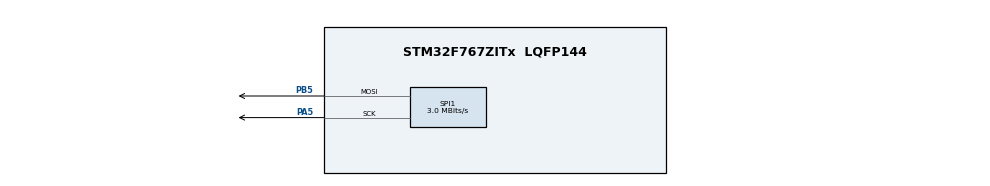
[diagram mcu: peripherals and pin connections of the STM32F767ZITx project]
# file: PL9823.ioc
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Dma.Request0=SPI1_TX
Dma.SPI1_TX.0.Direction=DMA_MEMORY_TO_PERIPH
Dma.SPI1_TX.0.FIFOMode=DMA_FIFOMODE_DISABLE
Dma.SPI1_TX.0.Instance=DMA2_Stream3
Dma.SPI1_TX.0.MemDataAlignment=DMA_MDATAALIGN_BYTE
Dma.SPI1_TX.0.MemInc=DMA_MINC_ENABLE
Dma.SPI1_TX.0.Mode=DMA_CIRCULAR
Dma.SPI1_TX.0.PeriphDataAlignment=DMA_PDATAALIGN_BYTE
Dma.SPI1_TX.0.PeriphInc=DMA_PINC_DISABLE
Dma.SPI1_TX.0.Priority=DMA_PRIORITY_VERY_HIGH
Mcu.Family=STM32F7
Mcu.Name=STM32F767ZITx
Mcu.Package=LQFP144
NVIC.DMA2_Stream3_IRQn=true\:0\:0\:false\:false\:true\:false\:true
NVIC.PriorityGroup=NVIC_PRIORITYGROUP_4
NVIC.SPI1_IRQn=true\:0\:0\:false\:false\:true\:true\:true
PA5.Mode=TX_Only_Simplex_Unidirect_Master
PA5.Signal=SPI1_SCK
PB5.Mode=TX_Only_Simplex_Unidirect_Master
PB5.Signal=SPI1_MOSI
ProjectManager.HeapSize=0x200
ProjectManager.StackSize=0x400
ProjectManager.TargetToolchain=TrueSTUDIO
RCC.AHBCLKDivider=RCC_SYSCLK_DIV4
RCC.AHBFreq_Value=24000000
RCC.APB1Freq_Value=24000000
RCC.APB1TimFreq_Value=24000000
RCC.APB2Freq_Value=24000000
RCC.APB2TimFreq_Value=24000000
RCC.CortexFreq_Value=24000000
RCC.HCLKFreq_Value=24000000
RCC.HSE_VALUE=25000000
RCC.HSI_VALUE=16000000
RCC.LSE_VALUE=32768
RCC.PLLM=8
RCC.PLLN=96
RCC.SYSCLKFreq_VALUE=96000000
RCC.SYSCLKSource=RCC_SYSCLKSOURCE_PLLCLK
RCC.USBFreq_Value=96000000
RCC.VCOOutputFreq_Value=192000000
SPI1.BaudRatePrescaler=SPI_BAUDRATEPRESCALER_8
SPI1.CalculateBaudRate=3.0 MBits/s
SPI1.DataSize=SPI_DATASIZE_8BIT
SPI1.Direction=SPI_DIRECTION_2LINES
SPI1.Mode=SPI_MODE_MASTER
SPI1.VirtualType=VM_MASTER
board=custom

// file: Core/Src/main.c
/* USER CODE BEGIN Header */
/**
 ******************************************************************************
 * @file           : main.c
 * @brief          : Main program body
 ******************************************************************************
 * @attention
 *
 * <h2><center>&copy; Copyright (c) 2020 STMicroelectronics.
 * All rights reserved.</center></h2>
 *
 * This software component is licensed by ST under BSD 3-Clause license,
 * the "License"; You may not use this file except in compliance with the
 * License. You may obtain a copy of the License at:
 *                        opensource.org/licenses/BSD-3-Clause
 *
 ******************************************************************************
 */
/* USER CODE END Header */
#include "main.h"

/* USER CODE BEGIN PD */
#define T0H 0b10000000
#define T1H 0b11110000
#define NUMBER_OF_LEDS 4
/* USER CODE END PD */

SPI_HandleTypeDef hspi1;
DMA_HandleTypeDef hdma_spi1_tx;

/* USER CODE BEGIN PV */
static uint8_t buffer[72];
/* USER CODE END PV */

void SystemClock_Config(void);
static void MX_GPIO_Init(void);
static void MX_DMA_Init(void);
static void MX_SPI1_Init(void);
/* USER CODE BEGIN PFP */
void LED_Random(void);
/* USER CODE END PFP */

/* USER CODE BEGIN 0 */

void LED_Random() {
	for (uint8_t i = 0; i < 72; i++)
		buffer[i] = random() % 256;
	HAL_SPI_Transmit(&hspi1, buffer, 72, 1000);
}
/* USER CODE END 0 */

int main(void)
{

  /* MCU Configuration--------------------------------------------------------*/

  /* Reset of all peripherals, Initializes the Flash interface and the Systick. */
  HAL_Init();

  /* Configure the system clock */
  SystemClock_Config();

  /* Initialize all configured peripherals */
  MX_GPIO_Init();
  MX_DMA_Init();
  MX_SPI1_Init();

  /* Infinite loop */
	while (1) {
		LED_Random();
		HAL_Delay(500);
	}
}

void SystemClock_Config(void)
{
  RCC_OscInitTypeDef RCC_OscInitStruct = {0};
  RCC_ClkInitTypeDef RCC_ClkInitStruct = {0};

  /** Configure the main internal regulator output voltage
  */
  __HAL_RCC_PWR_CLK_ENABLE();
  __HAL_PWR_VOLTAGESCALING_CONFIG(PWR_REGULATOR_VOLTAGE_SCALE3);
  /** Initializes the RCC Oscillators according to the specified parameters
  * in the RCC_OscInitTypeDef structure.
  */
  RCC_OscInitStruct.OscillatorType = RCC_OSCILLATORTYPE_HSI;
  RCC_OscInitStruct.HSIState = RCC_HSI_ON;
  RCC_OscInitStruct.HSICalibrationValue = RCC_HSICALIBRATION_DEFAULT;
  RCC_OscInitStruct.PLL.PLLState = RCC_PLL_ON;
  RCC_OscInitStruct.PLL.PLLSource = RCC_PLLSOURCE_HSI;
  RCC_OscInitStruct.PLL.PLLM = 8;
  RCC_OscInitStruct.PLL.PLLN = 96;
  RCC_OscInitStruct.PLL.PLLP = RCC_PLLP_DIV6;
  RCC_OscInitStruct.PLL.PLLQ = 2;
  if (HAL_RCC_OscConfig(&RCC_OscInitStruct) != HAL_OK)
  {
    Error_Handler();
  }
  /** Initializes the CPU, AHB and APB buses clocks
  */
  RCC_ClkInitStruct.ClockType = RCC_CLOCKTYPE_HCLK|RCC_CLOCKTYPE_SYSCLK
                              |RCC_CLOCKTYPE_PCLK1|RCC_CLOCKTYPE_PCLK2;
  RCC_ClkInitStruct.SYSCLKSource = RCC_SYSCLKSOURCE_PLLCLK;
  RCC_ClkInitStruct.AHBCLKDivider = RCC_SYSCLK_DIV2;
  RCC_ClkInitStruct.APB1CLKDivider = RCC_HCLK_DIV1;
  RCC_ClkInitStruct.APB2CLKDivider = RCC_HCLK_DIV1;

  if (HAL_RCC_ClockConfig(&RCC_ClkInitStruct, FLASH_LATENCY_0) != HAL_OK)
  {
    Error_Handler();
  }
}

static void MX_SPI1_Init(void)
{

  /* SPI1 parameter configuration*/
  hspi1.Instance = SPI1;
  hspi1.Init.Mode = SPI_MODE_MASTER;
  hspi1.Init.Direction = SPI_DIRECTION_2LINES;
  hspi1.Init.DataSize = SPI_DATASIZE_8BIT;
  hspi1.Init.CLKPolarity = SPI_POLARITY_LOW;
  hspi1.Init.CLKPhase = SPI_PHASE_1EDGE;
  hspi1.Init.NSS = SPI_NSS_SOFT;
  hspi1.Init.BaudRatePrescaler = SPI_BAUDRATEPRESCALER_8;
  hspi1.Init.FirstBit = SPI_FIRSTBIT_MSB;
  hspi1.Init.TIMode = SPI_TIMODE_DISABLE;
  hspi1.Init.CRCCalculation = SPI_CRCCALCULATION_DISABLE;
  hspi1.Init.CRCPolynomial = 7;
  hspi1.Init.CRCLength = SPI_CRC_LENGTH_DATASIZE;
  hspi1.Init.NSSPMode = SPI_NSS_PULSE_ENABLE;
  if (HAL_SPI_Init(&hspi1) != HAL_OK)
  {
    Error_Handler();
  }

}

static void MX_DMA_Init(void)
{

  /* DMA controller clock enable */
  __HAL_RCC_DMA2_CLK_ENABLE();

  /* DMA interrupt init */
  /* DMA2_Stream3_IRQn interrupt configuration */
  HAL_NVIC_SetPriority(DMA2_Stream3_IRQn, 0, 0);
  HAL_NVIC_EnableIRQ(DMA2_Stream3_IRQn);

}

static void MX_GPIO_Init(void)
{

  /* GPIO Ports Clock Enable */
  __HAL_RCC_GPIOA_CLK_ENABLE();
  __HAL_RCC_GPIOB_CLK_ENABLE();

}

void Error_Handler(void)
{
	__disable_irq();
	while (1) {
	}
}

/************************ (C) COPYRIGHT STMicroelectronics *****END OF FILE****/
